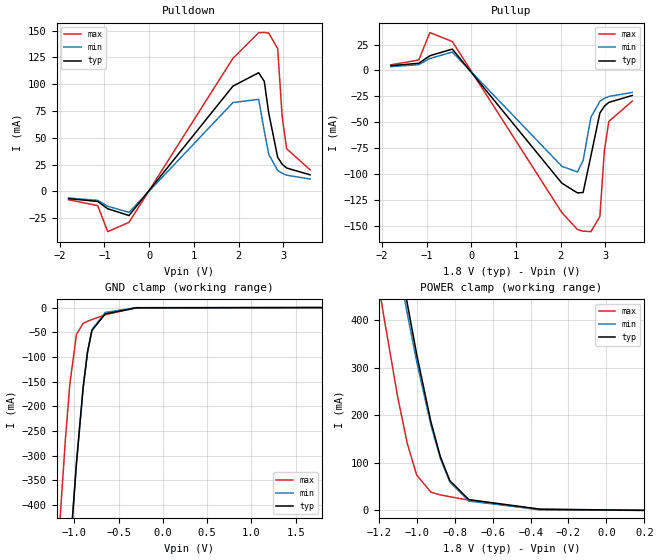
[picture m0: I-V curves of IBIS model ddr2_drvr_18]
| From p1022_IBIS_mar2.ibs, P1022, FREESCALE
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| * P1022 DDR2 Driver Model - 18 Ohm Setting *
[Model]   ddr2_drvr_18
Model_type I/O
Polarity   Non-Inverting
Vinl = 0.7V
Vinh = 1.1V
Vmeas = 0.9V
Cref = 0
Rref = 50
Vref = 0.9V
|   typ   min   max
C_comp   3.628585e-12   2.023030e-12   4.796450e-12
|   typ   min   max
[Voltage range]   1.8V   1.7V   1.9V
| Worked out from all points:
|   slope of the pulldown table from 0 to 0.27 V, typ, clamps not added: 18 ohm
|   slope of the pullup table from 0 to 0.27 V, typ, clamps not added: 17.7 ohm
|   GND clamp passes 1 mA (typ) near -0.33 V on its own axis
|   POWER clamp passes 1 mA (typ) near -0.28 V on its own axis
[Pulldown]
| Warnings regarding non-monotonicity are expected
| Voltage   I(typ)   I(min)   I(max)
-1.8V     -6.746mA   -6.162mA   -7.796mA
-1.15V    -9.335mA   -8.313mA   -13.2mA
-925mV    -16.16mA   -13.83mA   -37.52mA
-450mV    -22.5mA    -19.54mA   -28.84mA
1.875V    98.24mA    82.92mA    124.2mA
2.45V     110.7mA    85.89mA    148.1mA
2.575V    102.7mA    56.47mA    148.2mA
2.675V    73.03mA    34.59mA    147.7mA
2.875V    31.76mA    19.57mA    133.1mA
2.975V    25.37mA    16.84mA    69.86mA
3.075V    21.82mA    15.13mA    39.85mA
3.6V      15.48mA    11.56mA    20.11mA
[GND_clamp]
| Voltage   I(typ)   I(min)   I(max)
-1.8V     -2.78A     -2.734A    -2.433A
-1.2V     -918.5mA   -909.4mA   -538.8mA
-1.175V   -846mA     -838.3mA   -467.5mA
-1.1V     -634.6mA   -630.8mA   -267.7mA
-1.05V    -500.5mA   -498.8mA   -155.7mA
-975mV    -315.3mA   -316.1mA   -54.58mA
-900mV    -162.7mA   -164.1mA   -32.05mA
-850mV    -90.19mA   -90.35mA   -27.79mA
-800mV    -46.39mA   -44.74mA   -24.31mA
-650mV    -12.83mA   -9.896mA   -14.51mA
-300mV    -558.6uA   -261.1uA   -231.9uA
1.8V      1.714uA    9.547uA    12.62nA
[Pullup]
| Warnings regarding non-monotonicity are expected
| Voltage   I(typ)   I(min)   I(max)
-1.8V     4.562mA    3.65mA     5.38mA
-1.175V   6.927mA    5.587mA    10.07mA
-925mV    14.22mA    11.52mA    36.61mA
-425mV    20.62mA    17.82mA    27.94mA
2.025V    -108.9mA   -92.58mA   -137.3mA
2.375V    -118.3mA   -98.07mA   -153.7mA
2.5V      -117.9mA   -87.06mA   -155.2mA
2.675V    -82.42mA   -45.19mA   -155.7mA
2.875V    -41.11mA   -29.88mA   -141.1mA
2.975V    -34.56mA   -26.98mA   -77.7mA
3.075V    -30.86mA   -25.14mA   -49.24mA
3.6V      -24.16mA   -21.23mA   -29.56mA
[POWER_clamp]
| Warnings about POWER_clamp data never reaching
| zero are expected, and this is okay as long as
| the 0V data are around 10uA or less
| Voltage   I(typ)   I(min)   I(max)
-1.8V     2.412A     2.266A     2.142A
-1.2V     797.2mA    753.3mA    475mA
-1.175V   734.5mA    694.6mA    412.6mA
-1.1V     552mA      523.4mA    238.4mA
-1.05V    436.4mA    415mA      141.5mA
-1V       328.1mA    313.2mA    74.16mA
-925mV    186.2mA    179.4mA    38.2mA
-875mV    112.7mA    109.2mA    32.53mA
-825mV    62.3mA     59.8mA     28.63mA
-725mV    22.56mA    19.44mA    21.45mA
-350mV    2.574mA    1.808mA    967.2uA
200mV     0A         0A         0A
|   typ   min   max
[Ramp]
dV/dt_r  0.798825/8.14659e-11   0.720897/1.17052E-10   0.891541/3.45701E-11
dV/dt_f  0.795472/8.01555e-11   0.715934/1.14335E-10   0.887124/3.71123E-11
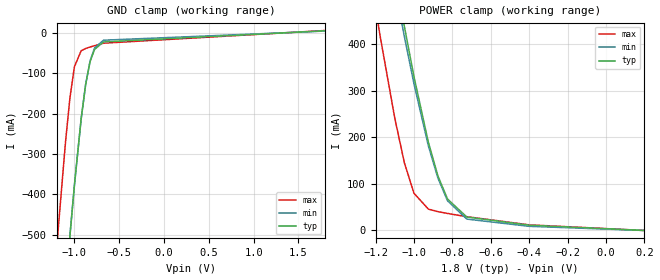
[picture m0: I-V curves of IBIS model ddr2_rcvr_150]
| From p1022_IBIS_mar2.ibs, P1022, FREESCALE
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| * P1022 DDR2 Receiver Model - 150 Ohm Termination *
[Model]   ddr2_rcvr_150
Model_type Input
Polarity   Non-Inverting
Vinl = 0.7V
Vinh = 1.1V
|   typ   min   max
C_comp   3.628490e-12   2.023010e-12   4.796400e-12
|   typ   min   max
[Voltage range]   1.8V   1.7V   1.9V
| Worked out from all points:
|   POWER clamp passes 1 mA (typ) near -0.00 V on its own axis
[GND_clamp]
| Voltage   I(typ)   I(min)   I(max)
-1.8V     -2.782A    -2.735A    -2.434A
-1.2V     -920.4mA   -911mA     -541.2mA
-1.175V   -848mA     -839.9mA   -470mA
-1.1V     -636.9mA   -632.6mA   -271mA
-1.05V    -503mA     -500.8mA   -160.1mA
-1V       -377.1mA   -376.7mA   -83.21mA
-925mV    -212.3mA   -213mA     -43.7mA
-875mV    -127.5mA   -127.4mA   -38.09mA
-825mV    -70.4mA    -68.46mA   -34.47mA
-775mV    -40.34mA   -36.68mA   -31.15mA
-675mV    -21.82mA   -17.52mA   -24.95mA
1.8V      5.871mA    5.164mA    6.592mA
[POWER_clamp]
| Table entry for 0V is set to 0.00 to avoid
| double counting with GND_clamp table
| Voltage   I(typ)   I(min)   I(max)
-1.8V     2.413A     2.266A     2.143A
-1.2V     798.6mA    754.4mA    476.9mA
-1.175V   736mA      695.7mA    414.6mA
-1.1V     553.8mA    524.7mA    241.2mA
-1.05V    438.4mA    416.4mA    145.4mA
-1V       330.4mA    314.9mA    79.86mA
-925mV    189.4mA    181.7mA    45.89mA
-875mV    116.8mA    112.1mA    40.43mA
-825mV    67.41mA    63.6mA     36.6mA
-725mV    29.02mA    24.48mA    29.61mA
-400mV    11.31mA    8.888mA    12.09mA
200mV     0A         0A         0A
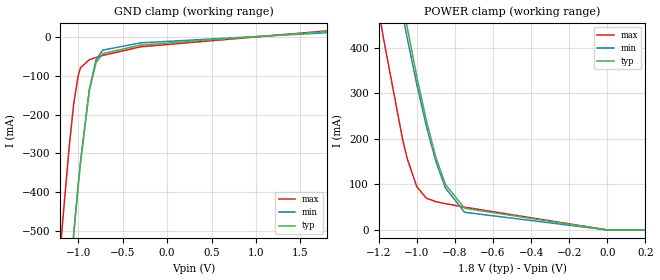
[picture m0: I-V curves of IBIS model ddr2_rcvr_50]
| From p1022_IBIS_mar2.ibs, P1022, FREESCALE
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| * P1022 DDR2 Receiver Model - 50 Ohm Termination *
[Model]   ddr2_rcvr_50
Model_type Input
Polarity   Non-Inverting
Vinl = 0.7V
Vinh = 1.1V
|   typ   min   max
C_comp   3.628490e-12   2.023010e-12   4.796400e-12
|   typ   min   max
[Voltage range]   1.8V   1.7V   1.9V
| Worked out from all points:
|   POWER clamp passes 1 mA (typ) near -0.00 V on its own axis
[GND_clamp]
| Voltage   I(typ)   I(min)   I(max)
-1.8V     -2.785A    -2.737A    -2.438A
-1.2V     -925mA     -914.4mA   -547.2mA
-1.175V   -852.7mA   -843.4mA   -476.4mA
-1.1V     -642.2mA   -636.4mA   -279.3mA
-1.05V    -508.8mA   -505mA     -171.1mA
-1V       -383.8mA   -381.5mA   -98.69mA
-975mV    -325.5mA   -323.6mA   -79.39mA
-875mV    -138.1mA   -134.7mA   -58.15mA
-800mV    -66.25mA   -59.04mA   -52.52mA
-725mV    -42.51mA   -33.45mA   -47.22mA
-300mV    -20.3mA    -14.57mA   -24.9mA
1.8V      14.63mA    11.58mA    16.44mA
[POWER_clamp]
| Table entry for 0V is set to 0.00 to avoid
| double counting with GND_clamp table
| Voltage   I(typ)   I(min)   I(max)
-1.8V     2.415A     2.268A     2.146A
-1.2V     802mA      756.6mA    481.7mA
-1.175V   739.6mA    698mA      419.8mA
-1.075V   499.7mA    472.8mA    198.8mA
-1.05V    443.1mA    419.5mA    155.5mA
-1V       335.8mA    318.5mA    94.54mA
-950mV    239.4mA    227.2mA    69.71mA
-900mV    158.8mA    150.1mA    62.05mA
-850mV    99.64mA    92.1mA     57.76mA
-750mV    47.73mA    38.84mA    50.16mA
0V        0A         0A         0A
200mV     0A         0A         0A
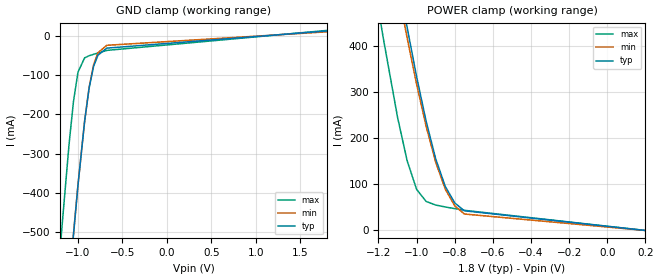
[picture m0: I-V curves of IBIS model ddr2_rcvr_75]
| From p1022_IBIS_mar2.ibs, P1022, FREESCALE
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[Model]   ddr2_rcvr_75
Model_type Input
Polarity   Non-Inverting
Vinl = 0.7V
Vinh = 1.1V
|   typ   min   max
C_comp   3.628490e-12   2.023010e-12   4.796400e-12
|   typ   min   max
[Voltage range]   1.8V   1.7V   1.9V
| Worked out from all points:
|   POWER clamp passes 1 mA (typ) near -0.00 V on its own axis
[GND_clamp]
| Voltage   I(typ)   I(min)   I(max)
-1.8V     -2.784A    -2.737A    -2.437A
-1.2V     -923.3mA   -913.3mA   -544.9mA
-1.175V   -851mA     -842.3mA   -474mA
-1.1V     -640.2mA   -635.2mA   -276.3mA
-1.05V    -506.7mA   -503.7mA   -167.1mA
-1V       -381.4mA   -379.9mA   -93.11mA
-925mV    -217.9mA   -217.1mA   -56.6mA
-875mV    -134.4mA   -132.4mA   -51.27mA
-825mV    -78.77mA   -74.51mA   -47.63mA
-775mV    -49.84mA   -43.53mA   -44.22mA
-675mV    -31.86mA   -24.65mA   -37.61mA
1.8V      11.72mA    9.581mA    13.22mA
[POWER_clamp]
| Table entry for 0V is set to 0.00 to avoid
| double counting with GND_clamp table
| Voltage   I(typ)   I(min)   I(max)
-1.8V     2.414A     2.267A     2.145A
-1.2V     800.7mA    755.8mA    479.8mA
-1.175V   738.2mA    697.2mA    417.8mA
-1.1V     556.3mA    526.5mA    245.6mA
-1.05V    441.3mA    418.5mA    151.7mA
-1V       333.8mA    317.3mA    89.09mA
-950mV    237mA      225.8mA    63.04mA
-900mV    155.7mA    148.2mA    55.21mA
-850mV    95.74mA    89.76mA    51.05mA
-800mV    59.83mA    53.49mA    47.39mA
-750mV    42.75mA    35.74mA    43.82mA
200mV     0A         0A         0A
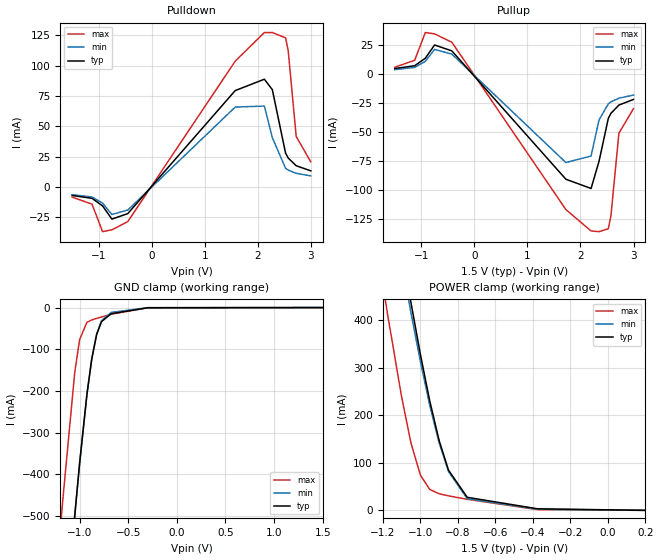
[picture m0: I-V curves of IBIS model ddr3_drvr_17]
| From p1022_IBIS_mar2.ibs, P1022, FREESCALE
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| * P1022 DDR3 Driver Model - 17 Ohm Setting *
[Model]   ddr3_drvr_17
Model_type I/O
Polarity   Non-Inverting
Vinl = 0.575V
Vinh = 0.925V
Vmeas = 0.75V
Cref = 0
Rref = 50
Vref = 0.75V
|   typ   min   max
C_comp   3.648430e-12   2.038680e-12   4.817870e-12
|   typ   min   max
[Voltage range]   1.5V   1.4V   1.6V
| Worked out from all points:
|   slope of the pulldown table from 0 to 0.225 V, typ, clamps not added: 18.3 ohm
|   slope of the pullup table from 0 to 0.225 V, typ, clamps not added: 18 ohm
|   GND clamp passes 1 mA (typ) near -0.33 V on its own axis
|   POWER clamp passes 1 mA (typ) near -0.28 V on its own axis
[Pulldown]
| Warnings regarding non-monotonicity are expected
| Voltage   I(typ)   I(min)   I(max)
-1.5V     -6.943mA   -6.27mA    -8.283mA
-1.125V   -9.276mA   -8.191mA   -14.06mA
-925mV    -15.52mA   -13.22mA   -36.74mA
-750mV    -26.41mA   -22.64mA   -35.27mA
-450mV    -21.89mA   -18.94mA   -28.47mA
1.575V    79.47mA    65.9mA     103.7mA
2.125V    88.85mA    66.72mA    127.3mA
2.275V    80.21mA    40.73mA    127.3mA
2.525V    27.91mA    15.44mA    122.9mA
2.575V    23.89mA    13.96mA    112.1mA
2.725V    17.56mA    11.32mA    41.68mA
3V        13.34mA    9.202mA    20.75mA
[GND_clamp]
| Voltage   I(typ)   I(min)   I(max)
-1.5V     -1.83A     -1.803A    -1.463A
-1.2V     -918.5mA   -909.4mA   -538.8mA
-1.175V   -846mA     -838.3mA   -467.5mA
-1.05V    -500.5mA   -498.8mA   -155.7mA
-1V       -374.3mA   -374.5mA   -77.03mA
-925mV    -208.7mA   -210.1mA   -35.53mA
-875mV    -123mA     -123.8mA   -29.71mA
-825mV    -64.79mA   -64.04mA   -26.02mA
-775mV    -33.87mA   -31.49mA   -22.62mA
-675mV    -14.65mA   -11.59mA   -16.08mA
-300mV    -558.2uA   -260.8uA   -231.8uA
1.5V      1.426uA    9.416uA    7.097nA
[Pullup]
| Warnings regarding non-monotonicity are expected
| Voltage   I(typ)   I(min)   I(max)
-1.5V     4.946mA    3.957mA    6.022mA
-1.125V   7.341mA    5.906mA    12.1mA
-925mV    13.8mA     11.15mA    36.06mA
-750mV    25.28mA    21.42mA    34.91mA
-425mV    20.2mA     17.42mA    27.68mA
1.725V    -90.86mA   -76.41mA   -117.1mA
2.2V      -98.86mA   -70.77mA   -135.6mA
2.35V     -75.39mA   -39.55mA   -136.2mA
2.525V    -38.24mA   -25.66mA   -133.7mA
2.575V    -33.81mA   -23.91mA   -122.3mA
2.725V    -26.69mA   -20.71mA   -51mA
3V        -21.81mA   -18.04mA   -29.75mA
[POWER_clamp]
| Warnings about POWER_clamp data never reaching
| zero are expected, and this is okay as long as
| the 0V data are around 10uA or less
| Voltage   I(typ)   I(min)   I(max)
-1.5V     1.587A     1.494A     1.288A
-1.2V     797.2mA    753.3mA    475mA
-1.175V   734.5mA    694.6mA    412.6mA
-1.1V     552mA      523.4mA    238.4mA
-1.05V    436.4mA    415mA      141.5mA
-1V       328.1mA    313.2mA    74.16mA
-950mV    230mA      220.8mA    43.98mA
-900mV    146.9mA    141.9mA    34.88mA
-850mV    84.43mA    81.66mA    30.52mA
-750mV    27.4mA     24.37mA    23.21mA
-375mV    3.278mA    2.36mA     1.604mA
200mV     0A         0A         0A
|   typ   min   max
[Ramp]
dV/dt_r   0.66242/9.74685E-11   0.589801/1.44544E-10   0.74934/3.84995E-11
dV/dt_f   0.658119/9.00708E-11   0.583749/1.32332E-10   0.745099/3.75614E-11
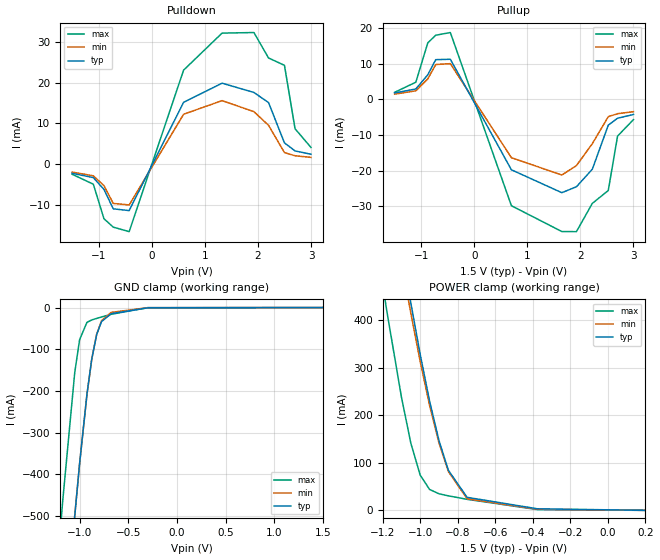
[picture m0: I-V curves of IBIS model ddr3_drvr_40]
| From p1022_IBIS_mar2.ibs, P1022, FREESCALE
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| * P1022 DDR3 Driver Model - 40 Ohm Setting *
[Model]   ddr3_drvr_40
Model_type I/O
Polarity   Non-Inverting
Vinl = 0.575V
Vinh = 0.925V
Vmeas = 0.75V
Cref = 0
Rref = 50
Vref = 0.75V
|   typ   min   max
C_comp   3.648330e-12   2.038670e-12   4.817820e-12
|   typ   min   max
[Voltage range]   1.5V   1.4V   1.6V
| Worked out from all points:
|   slope of the pulldown table from 0 to 0.225 V, typ, clamps not added: 33.1 ohm
|   slope of the pullup table from 0 to 0.225 V, typ, clamps not added: 30.3 ohm
|   GND clamp passes 1 mA (typ) near -0.33 V on its own axis
|   POWER clamp passes 1 mA (typ) near -0.28 V on its own axis
[Pulldown]
| Warnings regarding non-monotonicity are expected
| Voltage   I(typ)   I(min)   I(max)
-1.5V     -2.258mA   -1.956mA   -2.489mA
-1.1V     -3.315mA   -2.878mA   -4.935mA
-900mV    -6.212mA   -5.287mA   -13.42mA
-725mV    -10.99mA   -9.66mA    -15.49mA
-425mV    -11.42mA   -10.04mA   -16.6mA
600mV     15.19mA    12.26mA    23.1mA
1.325V    19.9mA     15.61mA    32.21mA
1.925V    17.62mA    12.9mA     32.35mA
2.2V      15.13mA    9.544mA    26.1mA
2.5V      5.232mA    2.832mA    24.29mA
2.7V      3.246mA    2.057mA    8.688mA
3V        2.432mA    1.653mA    4.1mA
[GND_clamp]
| Voltage   I(typ)   I(min)   I(max)
-1.5V     -1.83A     -1.803A    -1.463A
-1.2V     -918.5mA   -909.4mA   -538.8mA
-1.175V   -846mA     -838.3mA   -467.5mA
-1.05V    -500.5mA   -498.8mA   -155.7mA
-1V       -374.3mA   -374.5mA   -77.03mA
-925mV    -208.7mA   -210.1mA   -35.53mA
-875mV    -123mA     -123.8mA   -29.71mA
-825mV    -64.79mA   -64.04mA   -26.02mA
-775mV    -33.87mA   -31.49mA   -22.62mA
-675mV    -14.65mA   -11.59mA   -16.08mA
-300mV    -558.2uA   -260.8uA   -231.8uA
1.5V      1.426uA    9.416uA    6.886nA
[Pullup]
| Warnings regarding non-monotonicity are expected
| Voltage   I(typ)   I(min)   I(max)
-1.5V     1.812mA    1.473mA    1.978mA
-1.1V     2.927mA    2.406mA    4.821mA
-875mV    6.901mA    5.745mA    15.84mA
-725mV    11.14mA    9.776mA    17.99mA
-450mV    11.25mA    10.02mA    18.74mA
700mV     -19.72mA   -16.33mA   -29.79mA
1.65V     -26.14mA   -21.19mA   -37.03mA
1.925V    -24.49mA   -18.56mA   -37.06mA
2.225V    -19.55mA   -12.4mA    -29.13mA
2.525V    -7.227mA   -4.842mA   -25.54mA
2.7V      -5.272mA   -4.004mA   -10.28mA
3V        -4.225mA   -3.44mA    -5.653mA
[POWER_clamp]
| Warnings about POWER_clamp data never reaching
| zero are expected, and this is okay as long as
| the 0V data are around 10uA or less
| Voltage   I(typ)   I(min)   I(max)
-1.5V     1.587A     1.494A     1.288A
-1.2V     797.2mA    753.3mA    475mA
-1.175V   734.5mA    694.6mA    412.6mA
-1.1V     552mA      523.4mA    238.4mA
-1.05V    436.4mA    415mA      141.5mA
-1V       328.1mA    313.2mA    74.16mA
-950mV    230mA      220.8mA    43.98mA
-900mV    146.9mA    141.9mA    34.88mA
-850mV    84.43mA    81.66mA    30.52mA
-750mV    27.4mA     24.37mA    23.21mA
-375mV    3.278mA    2.36mA     1.604mA
200mV     0A         0A         0A
|   typ   min   max
[Ramp]
dV/dt_r   0.536878/2.15232E-10   0.461038/3.20165E-10   0.671656/8.51812E-11
dV/dt_f   0.493706/2.26258E-10   0.407757/3.36731E-10   0.639377/8.30845E-11
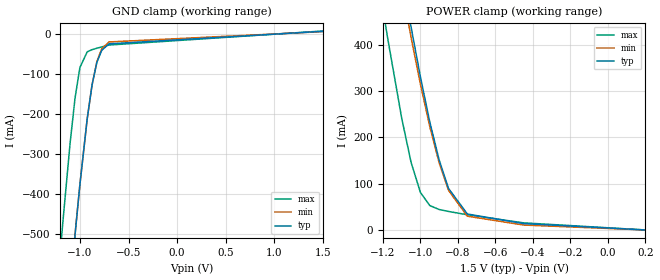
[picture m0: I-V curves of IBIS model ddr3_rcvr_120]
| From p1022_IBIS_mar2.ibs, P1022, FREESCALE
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| * P1022 DDR3 Receiver Model - 120 Ohm Termination *
[Model]   ddr3_rcvr_120
Model_type Input
Polarity   Non-Inverting
Vinl = 0.575V
Vinh = 0.925V
|   typ   min   max
C_comp   3.648330e-12   2.038670e-12   4.817820e-12
|   typ   min   max
[Voltage range]   1.5V   1.4V   1.6V
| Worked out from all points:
|   POWER clamp passes 1 mA (typ) near -0.00 V on its own axis
[GND_clamp]
| Voltage   I(typ)   I(min)   I(max)
-1.5V     -1.832A    -1.805A    -1.465A
-1.2V     -920.7mA   -911.2mA   -541.7mA
-1.175V   -848.4mA   -840.2mA   -470.6mA
-1.1V     -637.3mA   -632.9mA   -271.7mA
-1.05V    -503.4mA   -501.1mA   -161mA
-1V       -377.6mA   -377.1mA   -84.49mA
-925mV    -213mA     -213.5mA   -45.38mA
-875mV    -128.3mA   -128mA     -39.84mA
-825mV    -71.39mA   -69.16mA   -36.25mA
-775mV    -41.46mA   -37.48mA   -32.97mA
-700mV    -25.34mA   -20.58mA   -28.29mA
1.5V      6.036mA    5.221mA    6.835mA
[POWER_clamp]
| Table entry for 0V is set to 0.00 to avoid
| double counting with GND_clamp table
| Voltage   I(typ)   I(min)   I(max)
-1.5V     1.589A     1.495A     1.289A
-1.2V     798.8mA    754.5mA    477.3mA
-1.175V   736.3mA    695.8mA    415mA
-1.1V     554mA      524.8mA    241.7mA
-1.05V    438.7mA    416.6mA    146.2mA
-1V       330.7mA    315.1mA    80.96mA
-950mV    233.2mA    223.1mA    52.71mA
-900mV    151mA      144.8mA    44.23mA
-850mV    89.68mA    85.43mA    39.99mA
-750mV    34.57mA    29.77mA    32.91mA
-450mV    13.8mA     10.68mA    15.37mA
200mV     0A         0A         0A
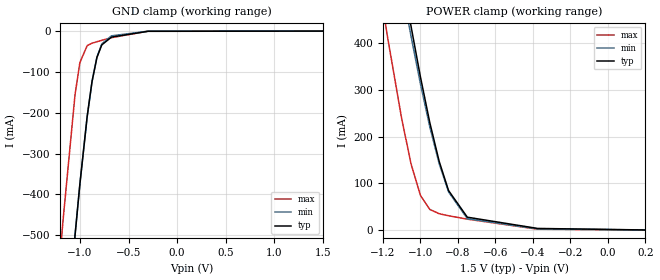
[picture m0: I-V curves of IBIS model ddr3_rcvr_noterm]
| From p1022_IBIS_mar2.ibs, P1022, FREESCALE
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| * P1022 DDR3 Receiver Model - No Termination  *
[Model]   ddr3_rcvr_noterm
Model_type Input
Polarity   Non-Inverting
Vinl = 0.575V
Vinh = 0.925V
|   typ   min   max
C_comp   3.648330e-12   2.038670e-12   4.817820e-12
|   typ   min   max
[Voltage range]   1.5V   1.4V   1.6V
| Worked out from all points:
|   GND clamp passes 1 mA (typ) near -0.33 V on its own axis
|   POWER clamp passes 1 mA (typ) near -0.28 V on its own axis
[GND_clamp]
| Voltage   I(typ)   I(min)   I(max)
-1.5V     -1.83A     -1.803A    -1.463A
-1.2V     -918.5mA   -909.4mA   -538.8mA
-1.175V   -846mA     -838.3mA   -467.5mA
-1.05V    -500.5mA   -498.8mA   -155.7mA
-1V       -374.3mA   -374.5mA   -77.03mA
-925mV    -208.7mA   -210.1mA   -35.53mA
-875mV    -123mA     -123.8mA   -29.71mA
-825mV    -64.79mA   -64.04mA   -26.02mA
-775mV    -33.87mA   -31.49mA   -22.62mA
-675mV    -14.65mA   -11.59mA   -16.08mA
-300mV    -558.2uA   -260.8uA   -231.8uA
1.5V      1.426uA    9.416uA    6.886nA
[POWER_clamp]
| Voltage   I(typ)   I(min)   I(max)
-1.5V     1.587A     1.494A     1.288A
-1.2V     797.2mA    753.3mA    475mA
-1.175V   734.5mA    694.6mA    412.6mA
-1.1V     552mA      523.4mA    238.4mA
-1.05V    436.4mA    415mA      141.5mA
-1V       328.1mA    313.2mA    74.16mA
-950mV    230mA      220.8mA    43.98mA
-900mV    146.9mA    141.9mA    34.88mA
-850mV    84.43mA    81.66mA    30.52mA
-750mV    27.4mA     24.37mA    23.21mA
-375mV    3.278mA    2.36mA     1.604mA
200mV     0A         0A         0A
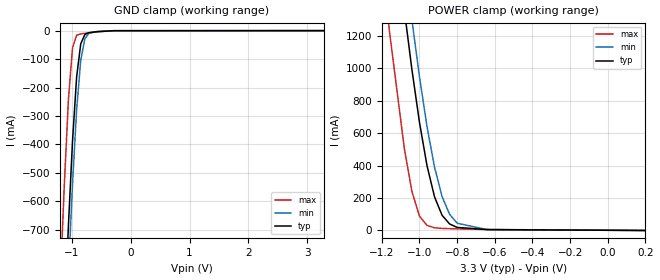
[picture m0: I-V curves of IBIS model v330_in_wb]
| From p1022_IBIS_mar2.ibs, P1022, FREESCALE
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|   Model v330_in_wb
[Model]   v330_in_wb
Model_type   Input
Polarity   Non-Inverting
Enable   Active-High
Vinl = 0.8V
Vinh = 2.0V
C_comp   3.0088pF   2.9071pF   3.0187pF
[Temperature Range]   85.0000   0.1250k   -40.0000
[Voltage Range]   3.3000V   3.0000V   3.6000V
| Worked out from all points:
|   GND clamp passes 1 mA (typ) near -0.40 V on its own axis
|   POWER clamp passes 1 mA (typ) near -0.36 V on its own axis
[GND_clamp]
|Voltage   I(typ)   I(min)   I(max)
-3.3V     -13.73A    -13.82A    -13.4A
-1.2V     -1.391A    -1.566A    -897.9mA
-1.13V    -1.029A    -1.202A    -545.5mA
-1.06V    -689.1mA   -856mA     -244.2mA
-990mV    -389.4mA   -540.8mA   -60.29mA
-920mV    -162.7mA   -278.3mA   -16.12mA
-850mV    -46.12mA   -103.3mA   -11.28mA
-780mV    -13.43mA   -28.48mA   -9.313mA
-710mV    -6.961mA   -8.948mA   -7.513mA
-570mV    -3.535mA   -2.898mA   -4.119mA
-290mV    -172.2uA   -118uA     -100.6uA
3.28V     33.17uA    318.9uA    41.47uA
[POWER_clamp]
|Voltage   I(typ)   I(min)   I(max)
-3.28V    27.57A     27.6A      27.12A
-1.16V    2.159A     2.491A     1.232A
-1.08V    1.354A     1.674A     501.9mA
-1.04V    989.9mA    1.296A     239.7mA
-1V       666.1mA    947mA      88.09mA
-960mV    399.3mA    640.1mA    31.31mA
-920mV    207mA      389.6mA    16.45mA
-880mV    93.64mA    209mA      12.75mA
-840mV    40.2mA     99.66mA    11.23mA
-800mV    18.85mA    44.69mA    10.1mA
-640mV    5.419mA    5.214mA    6.004mA
200mV     0A         0A         0A
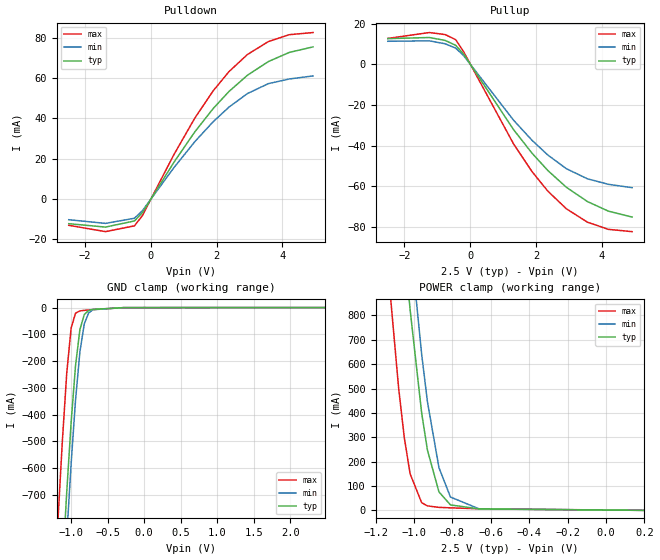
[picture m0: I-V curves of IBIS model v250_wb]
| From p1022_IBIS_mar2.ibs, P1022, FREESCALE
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|   Model v250_wb
[Model]   v250_wb
Model_type   I/O
Polarity   Non-Inverting
Enable   Active-High
Vinl = 0.7V
Vinh = 1.7V
Vmeas =1.25V
Cref = 0
Rref = 50
Vref = 1.25V
C_comp   3.0088pF   2.9071pF   3.0187pF
[Temperature Range]   85.0000   0.1250k   -40.0000
[Voltage Range]   2.5000V   2.2500V   2.7500V
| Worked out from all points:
|   slope of the pulldown table from 0 to 0.375 V, typ, clamps not added: 38.1 ohm
|   slope of the pullup table from 0 to 0.375 V, typ, clamps not added: 39.1 ohm
|   GND clamp passes 1 mA (typ) near -0.40 V on its own axis
|   POWER clamp passes 1 mA (typ) near -0.37 V on its own axis
[Pulldown]
|Voltage   I(typ)   I(min)   I(max)
-2.5V     -12.21mA   -10.24mA   -13.01mA
-1.38V    -13.89mA   -12.06mA   -16.15mA
-500mV    -10.85mA   -9.519mA   -13.28mA
-260mV    -6.793mA   -5.842mA   -8.268mA
700mV     18.15mA    15.51mA    21.97mA
1.34V     33.32mA    28.46mA    40.15mA
1.9V      44.89mA    38.36mA    53.67mA
2.38V     53.32mA    45.57mA    63.15mA
2.94V     61.33mA    52.26mA    71.61mA
3.58V     68.14mA    57.19mA    78.04mA
4.22V     72.67mA    59.5mA     81.45mA
4.94V     75.4mA     61mA       82.5mA
[Pullup]
|Voltage   I(typ)   I(min)   I(max)
-2.5V     12.7mA     11.4mA     12.8mA
-1.24V    13.26mA    11.62mA    15.71mA
-760mV    11.82mA    10.17mA    14.71mA
-440mV    9.431mA    8.034mA    12.21mA
-200mV    5.111mA    4.372mA    6.304mA
1.32V     -32.2mA    -27.54mA   -39.25mA
1.88V     -43.79mA   -37.44mA   -52.88mA
2.36V     -52.34mA   -44.7mA    -62.5mA
2.92V     -60.56mA   -51.4mA    -71.17mA
3.56V     -67.62mA   -56.41mA   -77.8mA
4.2V      -72.37mA   -59.14mA   -81.35mA
4.92V     -75.3mA    -60.79mA   -82.47mA
[GND_clamp]
|Voltage   I(typ)   I(min)   I(max)
-2.5V     -8.959A    -9.088A    -8.56A
-1.18V    -1.286A    -1.46A     -794.1mA
-1.12V    -978.5mA   -1.151A    -498.3mA
-1.06V    -689.1mA   -856mA     -244.2mA
-1V       -428.7mA   -583.2mA   -76.41mA
-940mV    -217.3mA   -346mA     -20.8mA
-880mV    -82.19mA   -165.4mA   -12.47mA
-820mV    -25.87mA   -60.66mA   -10.38mA
-760mV    -10.48mA   -19.68mA   -8.788mA
-700mV    -6.565mA   -7.882mA   -7.257mA
-280mV    -139.5uA   -95.66uA   -76.3uA
2.48V     20.01uA    128uA      25.01uA
[POWER_clamp]
|Voltage   I(typ)   I(min)   I(max)
-2.49V    17.95A     18.09A     17.34A
-1.17V    2.265A     2.597A     1.335A
-1.14V    1.951A     2.281A     1.033A
-1.08V    1.354A     1.674A     501.9mA
-1.05V    1.078A     1.388A     295.7mA
-1.02V    822mA      1.117A     149.3mA
-960mV    399.3mA    640.1mA    31.29mA
-930mV    247.4mA    446.1mA    18.41mA
-870mV    75.77mA    175.4mA    12.27mA
-810mV    22.38mA    54.64mA    10.35mA
-660mV    5.855mA    5.94mA     6.475mA
200mV     0A         0A         0A
[Ramp]
| variable   typ   min   max
dV/dt_r  0.8278/0.3783n   0.6909/0.5385n   0.9929/0.2301n
dV/dt_f  0.8353/0.3549n   0.6974/0.4919n   0.9965/0.2324n
R_load = 50.0000
|End [Model] v250_wb
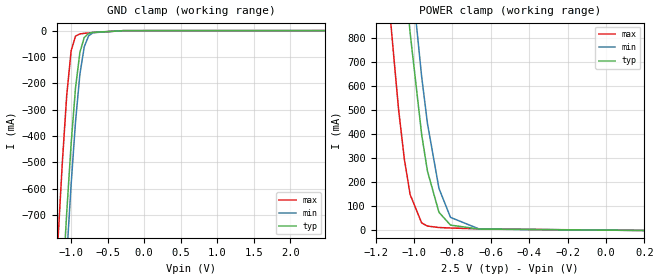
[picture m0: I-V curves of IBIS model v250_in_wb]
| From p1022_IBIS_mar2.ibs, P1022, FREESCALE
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|   Model v250_in_wb
[Model]   v250_in_wb
Model_type   Input
Polarity   Non-Inverting
Enable   Active-High
Vinl = 0.7V
Vinh = 1.7V
C_comp   3.0088pF   2.9071pF   3.0187pF
[Temperature Range]   85.0000   0.1250k   -40.0000
[Voltage Range]   2.5000V   2.2500V   2.7500V
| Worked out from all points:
|   GND clamp passes 1 mA (typ) near -0.40 V on its own axis
|   POWER clamp passes 1 mA (typ) near -0.37 V on its own axis
[GND_clamp]
|Voltage   I(typ)   I(min)   I(max)
-2.5V     -8.959A    -9.088A    -8.56A
-1.18V    -1.286A    -1.46A     -794.1mA
-1.12V    -978.5mA   -1.151A    -498.3mA
-1.06V    -689.1mA   -856mA     -244.2mA
-1V       -428.7mA   -583.2mA   -76.41mA
-940mV    -217.3mA   -346mA     -20.8mA
-880mV    -82.19mA   -165.4mA   -12.47mA
-820mV    -25.87mA   -60.66mA   -10.38mA
-760mV    -10.48mA   -19.68mA   -8.788mA
-700mV    -6.565mA   -7.882mA   -7.257mA
-280mV    -139.5uA   -95.66uA   -76.3uA
2.48V     20.01uA    128uA      25.01uA
[POWER_clamp]
|Voltage   I(typ)   I(min)   I(max)
-2.49V    17.95A     18.09A     17.34A
-1.17V    2.265A     2.597A     1.335A
-1.14V    1.951A     2.281A     1.033A
-1.08V    1.354A     1.674A     501.9mA
-1.05V    1.078A     1.388A     295.7mA
-1.02V    822mA      1.117A     149.3mA
-960mV    399.3mA    640.1mA    31.29mA
-930mV    247.4mA    446.1mA    18.41mA
-870mV    75.77mA    175.4mA    12.27mA
-810mV    22.38mA    54.64mA    10.35mA
-660mV    5.855mA    5.94mA     6.475mA
200mV     0A         0A         0A
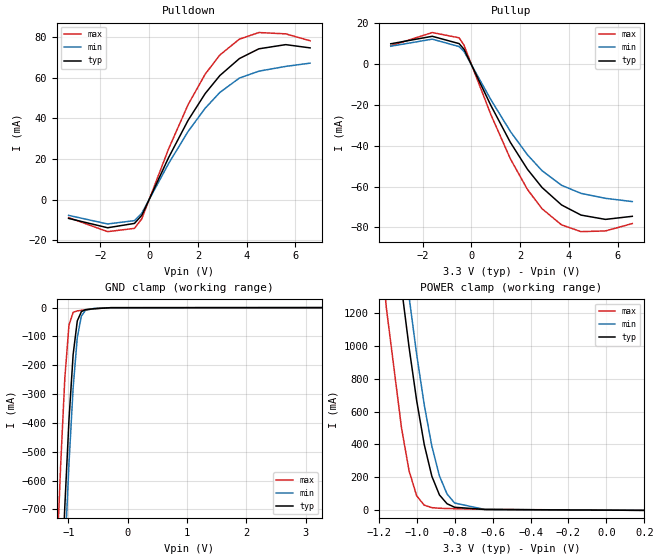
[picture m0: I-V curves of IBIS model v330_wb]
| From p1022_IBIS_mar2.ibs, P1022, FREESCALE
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|   Model v330_wb
[Model]   v330_wb
Model_type   I/O
Polarity   Non-Inverting
Enable   Active-High
Vinl = 0.8V
Vinh = 2.0V
Vmeas =1.65V
Cref = 0
Rref = 50
Vref = 1.65V
C_comp   3.0088pF   2.9071pF   3.0187pF
[Temperature Range]   85.0000   0.1250k   -40.0000
[Voltage Range]   3.3000V   3.0000V   3.6000V
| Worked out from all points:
|   slope of the pulldown table from 0 to 0.495 V, typ, clamps not added: 38.1 ohm
|   slope of the pullup table from 0 to 0.495 V, typ, clamps not added: 39.1 ohm
|   GND clamp passes 1 mA (typ) near -0.40 V on its own axis
|   POWER clamp passes 1 mA (typ) near -0.36 V on its own axis
[Pulldown]
|Voltage   I(typ)   I(min)   I(max)
-3.3V     -9.26mA    -7.77mA    -8.87mA
-1.7V     -13.86mA   -11.99mA   -15.77mA
-600mV    -11.72mA   -10.34mA   -14.17mA
-300mV    -7.744mA   -6.702mA   -9.456mA
800mV     20.68mA    17.74mA    24.96mA
1.6V      39.02mA    33.53mA    46.74mA
2.3V      52.16mA    44.95mA    61.71mA
2.9V      61mA       52.69mA    71.1mA
3.7V      69.34mA    59.76mA    78.9mA
4.5V      74.15mA    63.15mA    82.15mA
5.6V      76.2mA     65.5mA     81.5mA
6.6V      74.6mA     67.1mA     78.1mA
[Pullup]
|Voltage   I(typ)   I(min)   I(max)
-3.3V     10mA       8.8mA      9mA
-1.6V     13.68mA    12.28mA    15.52mA
-500mV    10.08mA    8.634mA    12.94mA
-300mV    7.35mA     6.277mA    9.343mA
800mV     -20.19mA   -17.36mA   -24.66mA
1.6V      -38.31mA   -32.96mA   -46.37mA
2.3V      -51.51mA   -44.42mA   -61.42mA
2.9V      -60.49mA   -52.24mA   -70.91mA
3.7V      -69.05mA   -59.42mA   -78.82mA
4.5V      -74.03mA   -63.37mA   -82.14mA
5.5V      -76.13mA   -65.8mA    -81.79mA
6.6V      -74.62mA   -67.39mA   -78.18mA
[GND_clamp]
|Voltage   I(typ)   I(min)   I(max)
-3.3V     -13.73A    -13.82A    -13.4A
-1.2V     -1.391A    -1.566A    -897.9mA
-1.13V    -1.029A    -1.202A    -545.5mA
-1.06V    -689.1mA   -856mA     -244.2mA
-990mV    -389.4mA   -540.8mA   -60.29mA
-920mV    -162.7mA   -278.3mA   -16.12mA
-850mV    -46.12mA   -103.3mA   -11.28mA
-780mV    -13.43mA   -28.48mA   -9.313mA
-710mV    -6.961mA   -8.948mA   -7.513mA
-570mV    -3.535mA   -2.898mA   -4.119mA
-290mV    -172.2uA   -118uA     -100.6uA
3.28V     33.17uA    318.9uA    41.47uA
[POWER_clamp]
|Voltage   I(typ)   I(min)   I(max)
-3.28V    27.57A     27.6A      27.12A
-1.16V    2.159A     2.491A     1.232A
-1.08V    1.354A     1.674A     501.9mA
-1.04V    989.9mA    1.296A     239.7mA
-1V       666.1mA    947mA      88.09mA
-960mV    399.3mA    640.1mA    31.31mA
-920mV    207mA      389.6mA    16.45mA
-880mV    93.64mA    209mA      12.75mA
-840mV    40.2mA     99.66mA    11.23mA
-800mV    18.85mA    44.69mA    10.1mA
-640mV    5.419mA    5.214mA    6.004mA
200mV     0A         0A         0A
[Ramp]
| variable   typ   min   max
dV/dt_r  1.0794/0.3594n   0.9114/0.4949n   1.2838/0.2259n
dV/dt_f  1.0889/0.3534n   0.9196/0.4732n   1.2879/0.2359n
R_load = 50.0000
|End
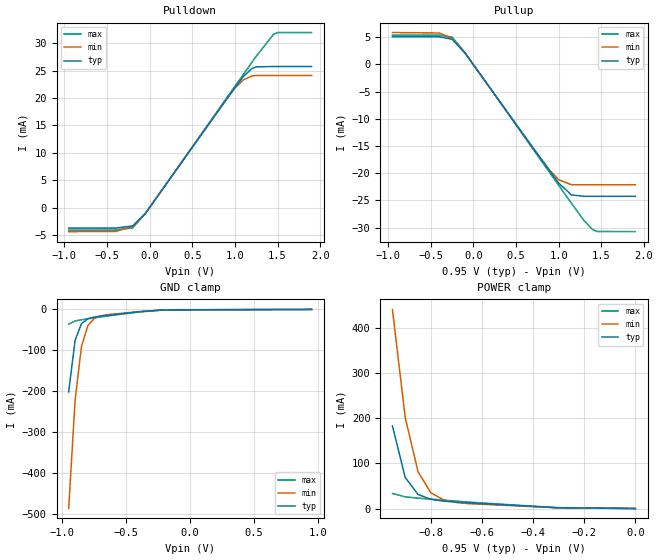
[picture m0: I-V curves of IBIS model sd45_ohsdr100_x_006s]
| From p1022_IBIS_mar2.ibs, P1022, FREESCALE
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[Model]   sd45_ohsdr100_x_006s
Model_type 3-state
Enable Active-High
Polarity Non-Inverting
|   TYP   MIN   MAX
C_comp   1.60pF   1.60pF   1.67pF
[Model Spec]
Vmeas   0.475   0.425   0.605
[Voltage Range]   0.95   0.85   1.21
[Temperature Range] 65   125   -40
[Driver Schedule]
| Model_Name  Rise_on_dly   Rise_off_dly   Fall_on_dly   Fall_off_dly
sd45_ohsdr100_x_00   0ps   NA   0ps   NA
sd45_ohsdr100_x_06   320ps   NA   320ps   NA
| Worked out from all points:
|   slope of the pulldown table from 0 to 0.142 V, typ, clamps not added: 45.5 ohm
|   slope of the pullup table from 0 to 0.142 V, typ, clamps not added: 45.4 ohm
|   GND clamp passes 1 mA (typ) near -0.19 V on its own axis
|   POWER clamp passes 1 mA (typ) near -0.25 V on its own axis
[Pullup]
|   Vout(V)   TYP   WCS   BCS
-950mV    5.093mA    5.874mA    5.386mA
-400mV    5.093mA    5.787mA    5.386mA
-250mV    4.634mA    4.784mA    5.037mA
-100mV    2.128mA    2.126mA    2.211mA
750mV     -16.46mA   -16.43mA   -16.69mA
900mV     -19.71mA   -19.54mA   -20.01mA
1V        -21.82mA   -21.19mA   -22.22mA
1.15V     -24mA      -22.13mA   -25.52mA
1.3V      -24.25mA   -22.13mA   -28.77mA
1.4V      -24.25mA   -22.13mA   -30.39mA
1.45V     -24.25mA   -22.13mA   -30.72mA
1.9V      -24.25mA   -22.13mA   -30.75mA
[Pulldown]
|   Vout(V)   TYP   WCS   BCS
-950mV    -3.758mA   -4.406mA   -4.109mA
-400mV    -3.758mA   -4.371mA   -4.109mA
-200mV    -3.361mA   -3.47mA    -3.717mA
-50mV     -1.064mA   -1.064mA   -1.095mA
900mV     19.7mA     19.76mA    19.92mA
1V        21.87mA    21.8mA     22.11mA
1.1V      23.93mA    23.32mA    24.31mA
1.2V      25.36mA    24.01mA    26.5mA
1.25V     25.67mA    24.1mA     27.6mA
1.45V     25.74mA    24.1mA     31.55mA
1.5V      25.74mA    24.1mA     31.94mA
1.9V      25.74mA    24.1mA     31.94mA
[GND Clamp]
|   Vout(V)   TYP   WCS   BCS
-950mV    -201.6mA   -486.5mA   -36.16mA
-900mV    -75.75mA   -222.9mA   -28.05mA
-850mV    -34.66mA   -90.59mA   -25.11mA
-800mV    -22.71mA   -39.37mA   -22.78mA
-750mV    -18.57mA   -21.91mA   -20.52mA
-700mV    -16.25mA   -15.71mA   -18.29mA
-650mV    -14.32mA   -12.88mA   -16.07mA
-400mV    -5.858mA   -5.175mA   -5.911mA
-200mV    -1.108mA   -1.072mA   -756.7uA
950mV     70.01uA    122.9uA    16.34uA
[POWER Clamp]
|   Vout(V)   TYP   WCS   BCS
-950mV    183.5mA    442.2mA    33.42mA
-900mV    68.86mA    202.2mA    25.88mA
-850mV    31.34mA    81.75mA    23.04mA
-800mV    20.35mA    35.06mA    20.76mA
-750mV    16.46mA    19.08mA    18.55mA
-700mV    14.22mA    13.35mA    16.36mA
-650mV    12.35mA    10.71mA    14.18mA
-300mV    1.805mA    1.56mA     1.409mA
0V        0A         0A         0A
[Ramp]
R_load=50.00
dV/dt_r  2.9887e-01/6.4040e-11  2.6861e-01/6.5155e-11  3.8214e-01/6.5744e-11
dV/dt_f  2.9887e-01/6.6355e-11  2.6861e-01/6.7761e-11  3.8218e-01/6.7348e-11
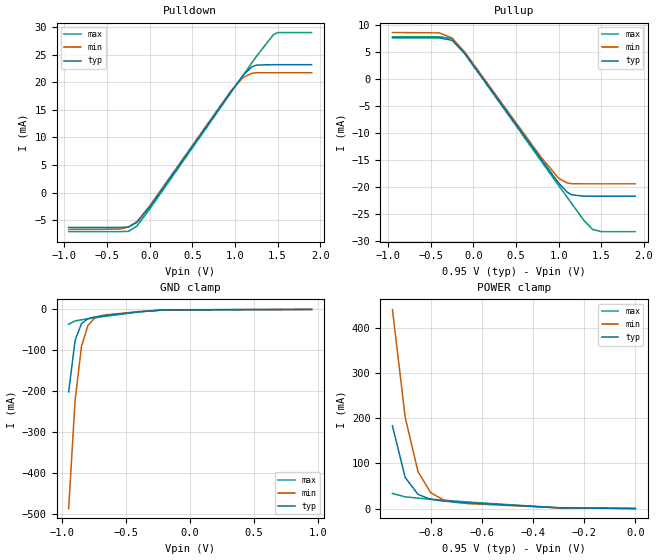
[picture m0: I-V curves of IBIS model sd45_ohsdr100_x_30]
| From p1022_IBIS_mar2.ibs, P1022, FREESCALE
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|Main and Boost models for Amp3: SRIOsr protocol
[Model]   sd45_ohsdr100_x_30
Model_type 3-state
Enable Active-High
Polarity Non-Inverting
|   TYP   MIN   MAX
C_comp   0.00pF   0.00pF   0.00pF
[Model Spec]
Vmeas   0.475   0.425   0.605
[Temperature Range] 65   125   -40
[Voltage Range]   0.95   0.85   1.21
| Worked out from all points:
|   slope of the pulldown table from 0 to 0.142 V, typ, clamps not added: 45.6 ohm
|   slope of the pullup table from 0 to 0.142 V, typ, clamps not added: 45.5 ohm
|   GND clamp passes 1 mA (typ) near -0.19 V on its own axis
|   POWER clamp passes 1 mA (typ) near -0.25 V on its own axis
[Pullup]
|   Vout(V)   TYP   WCS   BCS
-950mV    7.673mA    8.666mA    7.886mA
-400mV    7.673mA    8.608mA    7.886mA
-250mV    7.224mA    7.649mA    7.542mA
-100mV    4.728mA    5.025mA    4.721mA
800mV     -14.94mA   -14.6mA    -15.28mA
1V        -19.23mA   -18.36mA   -19.69mA
1.1V      -20.94mA   -19.22mA   -21.89mA
1.15V     -21.42mA   -19.37mA   -22.99mA
1.3V      -21.69mA   -19.39mA   -26.25mA
1.4V      -21.69mA   -19.39mA   -27.87mA
1.5V      -21.69mA   -19.39mA   -28.26mA
1.9V      -21.69mA   -19.39mA   -28.26mA
[Pulldown]
|   Vout(V)   TYP   WCS   BCS
-950mV    -6.32mA    -6.677mA   -7.074mA
-350mV    -6.32mA    -6.625mA   -7.074mA
-250mV    -6.223mA   -6.253mA   -7.019mA
-150mV    -5.42mA    -5.26mA    -6.077mA
0V        -2.59mA    -2.42mA    -2.989mA
950mV     18.18mA    18.36mA    18.02mA
1.1V      21.33mA    20.89mA    21.32mA
1.2V      22.77mA    21.6mA     23.52mA
1.25V     23.08mA    21.7mA     24.61mA
1.45V     23.16mA    21.7mA     28.57mA
1.5V      23.16mA    21.7mA     28.97mA
1.9V      23.16mA    21.7mA     28.98mA
[GND Clamp]
|   Vout(V)   TYP   WCS   BCS
-950mV    -201.6mA   -486.5mA   -36.16mA
-900mV    -75.75mA   -222.9mA   -28.05mA
-850mV    -34.66mA   -90.59mA   -25.11mA
-800mV    -22.71mA   -39.37mA   -22.78mA
-750mV    -18.57mA   -21.91mA   -20.52mA
-700mV    -16.25mA   -15.71mA   -18.29mA
-650mV    -14.32mA   -12.88mA   -16.07mA
-400mV    -5.858mA   -5.175mA   -5.911mA
-200mV    -1.108mA   -1.072mA   -756.7uA
950mV     70.01uA    122.9uA    16.34uA
[POWER Clamp]
|   Vout(V)   TYP   WCS   BCS
-950mV    183.5mA    442.2mA    33.42mA
-900mV    68.86mA    202.2mA    25.88mA
-850mV    31.34mA    81.75mA    23.04mA
-800mV    20.35mA    35.06mA    20.76mA
-750mV    16.45mA    19.08mA    18.55mA
-700mV    14.22mA    13.35mA    16.36mA
-650mV    12.35mA    10.71mA    14.18mA
-300mV    1.805mA    1.559mA    1.409mA
0V        0A         0A         0A
[Ramp]
R_load=50.00
dV/dt_r  2.2428e-01/6.4141e-11  1.9173e-01/6.5657e-11  3.0370e-01/6.5055e-11
dV/dt_f  2.2428e-01/6.6042e-11  1.9173e-01/6.8481e-11  3.0372e-01/6.6195e-11
|[End   sd45_ohsdr100_x_30
